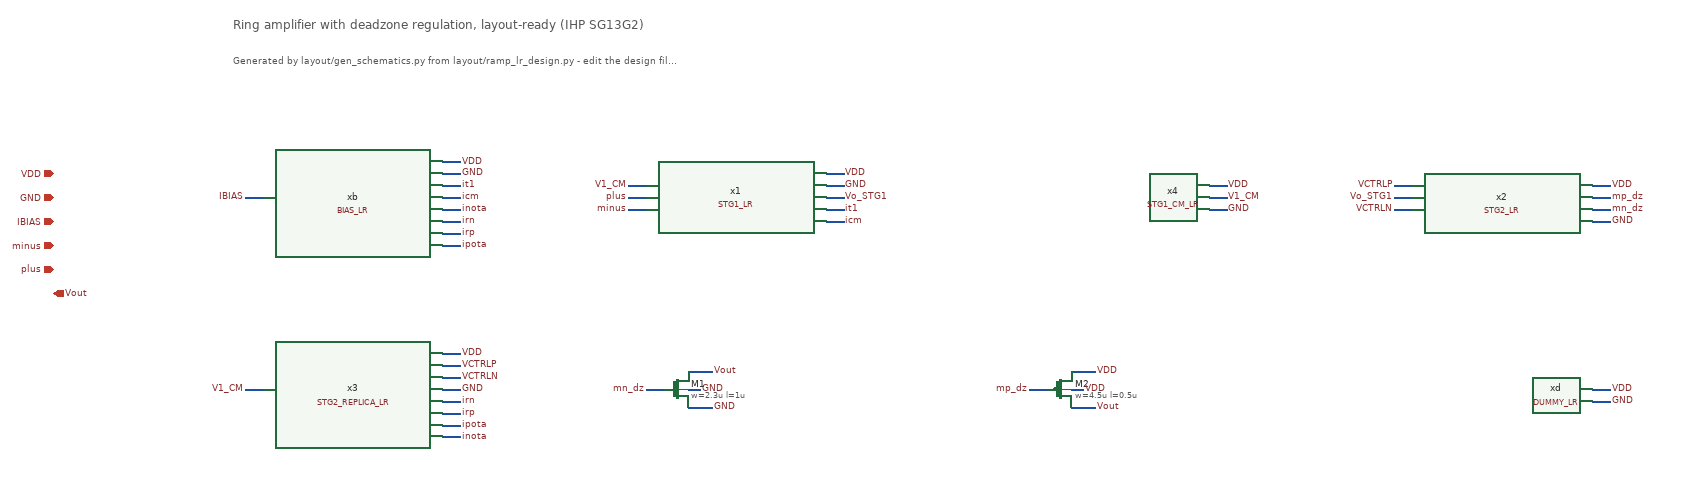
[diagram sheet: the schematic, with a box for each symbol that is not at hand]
v {xschem version=3.4.6 file_version=1.2}
G {}
K {}
V {}
S {}
E {}
T {Ring amplifier with deadzone regulation, layout-ready (IHP SG13G2)} 0 -260 0 0 0.6 0.6 {}
T {Generated by layout/gen_schematics.py from layout/ramp_lr_design.py - edit the design file, not this schematic} 0 -200 0 0 0.3 0.3 {}
C {iopin.sym} -300 0 0 0 {name=p1 lab=VDD}
C {iopin.sym} -300 40 0 0 {name=p2 lab=GND}
C {ipin.sym} -300 80 0 0 {name=p3 lab=IBIAS}
C {ipin.sym} -300 120 0 0 {name=p4 lab=minus}
C {ipin.sym} -300 160 0 0 {name=p5 lab=plus}
C {opin.sym} -300 200 0 0 {name=p6 lab=Vout}
C {RAMP-LR/BIAS_LR.sym} 200 40 0 0 {name=xb}
N 50 40 20 40 {lab=IBIAS}
C {lab_pin.sym} 20 40 0 0 {name=l1 sig_type=std_logic lab=IBIAS}
N 350 -20 380 -20 {lab=VDD}
C {lab_pin.sym} 380 -20 0 1 {name=l2 sig_type=std_logic lab=VDD}
N 350 0 380 0 {lab=GND}
C {lab_pin.sym} 380 0 0 1 {name=l3 sig_type=std_logic lab=GND}
N 350 20 380 20 {lab=it1}
C {lab_pin.sym} 380 20 0 1 {name=l4 sig_type=std_logic lab=it1}
N 350 40 380 40 {lab=icm}
C {lab_pin.sym} 380 40 0 1 {name=l5 sig_type=std_logic lab=icm}
N 350 60 380 60 {lab=inota}
C {lab_pin.sym} 380 60 0 1 {name=l6 sig_type=std_logic lab=inota}
N 350 80 380 80 {lab=irn}
C {lab_pin.sym} 380 80 0 1 {name=l7 sig_type=std_logic lab=irn}
N 350 100 380 100 {lab=irp}
C {lab_pin.sym} 380 100 0 1 {name=l8 sig_type=std_logic lab=irp}
N 350 120 380 120 {lab=ipota}
C {lab_pin.sym} 380 120 0 1 {name=l9 sig_type=std_logic lab=ipota}
C {RAMP-LR/STG1_LR.sym} 840 40 0 0 {name=x1}
N 690 20 660 20 {lab=V1_CM}
C {lab_pin.sym} 660 20 0 0 {name=l10 sig_type=std_logic lab=V1_CM}
N 690 40 660 40 {lab=plus}
C {lab_pin.sym} 660 40 0 0 {name=l11 sig_type=std_logic lab=plus}
N 690 60 660 60 {lab=minus}
C {lab_pin.sym} 660 60 0 0 {name=l12 sig_type=std_logic lab=minus}
N 990 0 1020 0 {lab=VDD}
C {lab_pin.sym} 1020 0 0 1 {name=l13 sig_type=std_logic lab=VDD}
N 990 20 1020 20 {lab=GND}
C {lab_pin.sym} 1020 20 0 1 {name=l14 sig_type=std_logic lab=GND}
N 990 40 1020 40 {lab=Vo_STG1}
C {lab_pin.sym} 1020 40 0 1 {name=l15 sig_type=std_logic lab=Vo_STG1}
N 990 60 1020 60 {lab=it1}
C {lab_pin.sym} 1020 60 0 1 {name=l16 sig_type=std_logic lab=it1}
N 990 80 1020 80 {lab=icm}
C {lab_pin.sym} 1020 80 0 1 {name=l17 sig_type=std_logic lab=icm}
C {RAMP-LR/STG1_CM_LR.sym} 1480 40 0 0 {name=x4}
N 1630 20 1660 20 {lab=VDD}
C {lab_pin.sym} 1660 20 0 1 {name=l18 sig_type=std_logic lab=VDD}
N 1630 40 1660 40 {lab=V1_CM}
C {lab_pin.sym} 1660 40 0 1 {name=l19 sig_type=std_logic lab=V1_CM}
N 1630 60 1660 60 {lab=GND}
C {lab_pin.sym} 1660 60 0 1 {name=l20 sig_type=std_logic lab=GND}
C {RAMP-LR/STG2_LR.sym} 2120 40 0 0 {name=x2}
N 1970 20 1940 20 {lab=VCTRLP}
C {lab_pin.sym} 1940 20 0 0 {name=l21 sig_type=std_logic lab=VCTRLP}
N 1970 40 1940 40 {lab=Vo_STG1}
C {lab_pin.sym} 1940 40 0 0 {name=l22 sig_type=std_logic lab=Vo_STG1}
N 1970 60 1940 60 {lab=VCTRLN}
C {lab_pin.sym} 1940 60 0 0 {name=l23 sig_type=std_logic lab=VCTRLN}
N 2270 20 2300 20 {lab=VDD}
C {lab_pin.sym} 2300 20 0 1 {name=l24 sig_type=std_logic lab=VDD}
N 2270 40 2300 40 {lab=mp_dz}
C {lab_pin.sym} 2300 40 0 1 {name=l25 sig_type=std_logic lab=mp_dz}
N 2270 60 2300 60 {lab=mn_dz}
C {lab_pin.sym} 2300 60 0 1 {name=l26 sig_type=std_logic lab=mn_dz}
N 2270 80 2300 80 {lab=GND}
C {lab_pin.sym} 2300 80 0 1 {name=l27 sig_type=std_logic lab=GND}
C {RAMP-LR/STG2_REPLICA_LR.sym} 200 360 0 0 {name=x3}
N 50 360 20 360 {lab=V1_CM}
C {lab_pin.sym} 20 360 0 0 {name=l28 sig_type=std_logic lab=V1_CM}
N 350 300 380 300 {lab=VDD}
C {lab_pin.sym} 380 300 0 1 {name=l29 sig_type=std_logic lab=VDD}
N 350 320 380 320 {lab=VCTRLP}
C {lab_pin.sym} 380 320 0 1 {name=l30 sig_type=std_logic lab=VCTRLP}
N 350 340 380 340 {lab=VCTRLN}
C {lab_pin.sym} 380 340 0 1 {name=l31 sig_type=std_logic lab=VCTRLN}
N 350 360 380 360 {lab=GND}
C {lab_pin.sym} 380 360 0 1 {name=l32 sig_type=std_logic lab=GND}
N 350 380 380 380 {lab=irn}
C {lab_pin.sym} 380 380 0 1 {name=l33 sig_type=std_logic lab=irn}
N 350 400 380 400 {lab=irp}
C {lab_pin.sym} 380 400 0 1 {name=l34 sig_type=std_logic lab=irp}
N 350 420 380 420 {lab=ipota}
C {lab_pin.sym} 380 420 0 1 {name=l35 sig_type=std_logic lab=ipota}
N 350 440 380 440 {lab=inota}
C {lab_pin.sym} 380 440 0 1 {name=l36 sig_type=std_logic lab=inota}
C {sg13g2_pr/sg13_hv_nmos.sym} 740 360 0 0 {name=M1
l=1u
w=2.3u
ng=1
m=4
model=sg13_hv_nmos
spiceprefix=X
}
N 760 330 800 330 {lab=Vout}
C {lab_pin.sym} 800 330 0 1 {name=l37 sig_type=std_logic lab=Vout}
N 760 390 800 390 {lab=GND}
C {lab_pin.sym} 800 390 0 1 {name=l38 sig_type=std_logic lab=GND}
N 760 360 780 360 {lab=GND}
C {lab_pin.sym} 780 360 0 1 {name=l39 sig_type=std_logic lab=GND}
N 720 360 690 360 {lab=mn_dz}
C {lab_pin.sym} 690 360 0 0 {name=l40 sig_type=std_logic lab=mn_dz}
C {sg13g2_pr/sg13_hv_pmos.sym} 1380 360 0 0 {name=M2
l=0.5u
w=4.5u
ng=1
m=4
model=sg13_hv_pmos
spiceprefix=X
}
N 1400 330 1440 330 {lab=VDD}
C {lab_pin.sym} 1440 330 0 1 {name=l41 sig_type=std_logic lab=VDD}
N 1400 390 1440 390 {lab=Vout}
C {lab_pin.sym} 1440 390 0 1 {name=l42 sig_type=std_logic lab=Vout}
N 1400 360 1420 360 {lab=VDD}
C {lab_pin.sym} 1420 360 0 1 {name=l43 sig_type=std_logic lab=VDD}
N 1360 360 1330 360 {lab=mp_dz}
C {lab_pin.sym} 1330 360 0 0 {name=l44 sig_type=std_logic lab=mp_dz}
C {RAMP-LR/DUMMY_LR.sym} 2120 360 0 0 {name=xd lvs_ignore=open}
N 2270 360 2300 360 {lab=VDD}
C {lab_pin.sym} 2300 360 0 1 {name=l45 sig_type=std_logic lab=VDD}
N 2270 380 2300 380 {lab=GND}
C {lab_pin.sym} 2300 380 0 1 {name=l46 sig_type=std_logic lab=GND}
C {title.sym} 0 760 0 0 {name=l0 author="Nithin Purushothama"}
